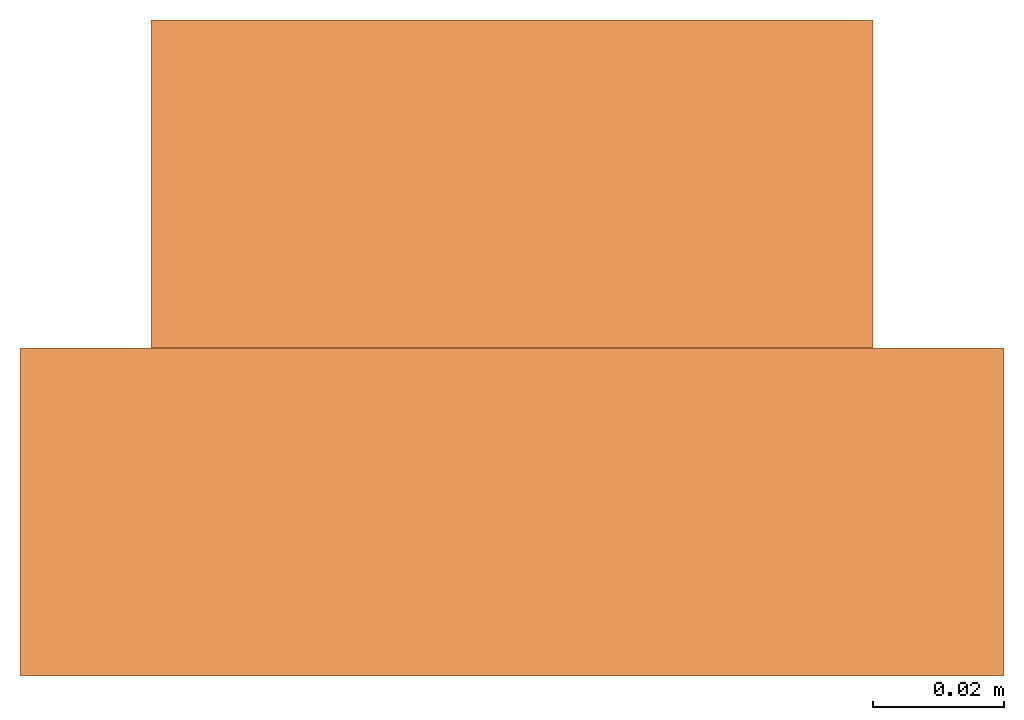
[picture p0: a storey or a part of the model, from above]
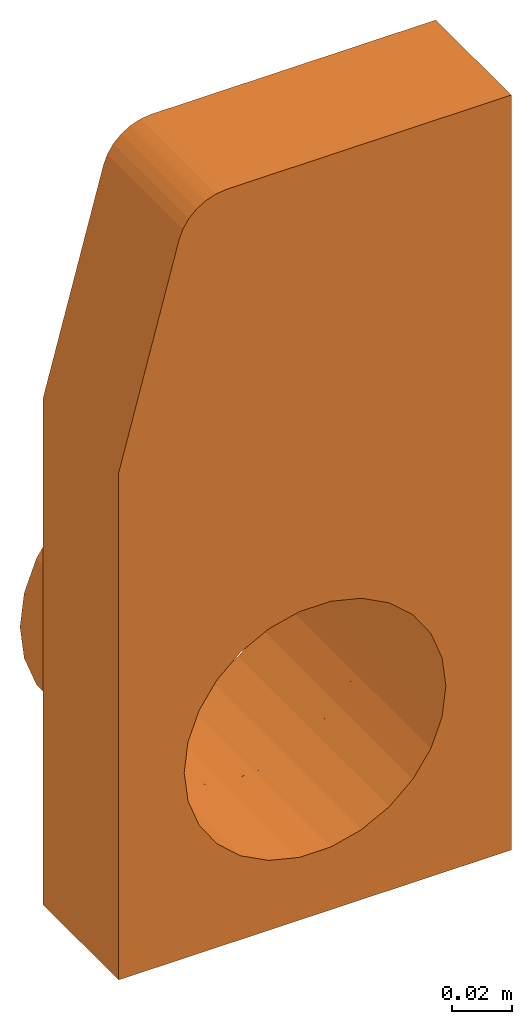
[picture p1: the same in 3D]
Properties of the parts of a building model (IFC2X3)

# File
Description: ViewDefinition [CoordinationView]
File name: 7963 - RH inlet or outlet end cap.ifc
Time: 2013-09-12T12:43:27
Written by: Autodesk Revit 2013
Made in: 20120221_2030(x64)

# IfcProject, Project Number
LongName: Project Name; Phase: Project Status

# IfcSite, Default
RefLatitude: 42, 21, 30, 344238; RefLongitude: -71, -3, -35, -194702; RefElevation: 0 mm

# IfcBuilding
Pset_BuildingCommon - NumberOfStoreys: 2
Other - Project Address: Enter address here; Project Number: Project Number; Client Name: Owner; Project Issue Date: Issue Date; Project Name: Project Name; Project Status: Project Status

# IfcBuildingStorey (2)
Constraints - Elevation Base: 0
Graphics - Line Pattern: Center; Color: 0; Symbol at End 2 Default: yes; Symbol at End 1 Default: no; Symbol: M_Level Head - Circle: M_Level Head - Circle; Line Weight: 1
Identity Data - Building Story: yes; Structural: no
Dimensions - Computation Height: 0 mm
Name | LongName = Name | Elevation (mm) = Constraints, Elevation (mm)
T.O. Fnd. Wall | T.O. Fnd. Wall | -300
Level 1 | Level 1 | 0

# IfcBuildingElementProxy: 7963 - RH inlet/outlet end cap, Civil-Drainage-Channel-ACO-KerbDrain-HB305 - PART 1:7963 - RH inlet/outlet end cap:7963 - RH inlet/outlet end cap:255899
In: T.O. Fnd. Wall
Material: ACO Polymer Concrete., Orange
Green Building Properties - Channel Recycled Material Content: N/A; Channel Recyclable: N/A; End Cap Recyclable: Fully recyclable; End Cap Recycled Material Content: 20% minimum; Access Cover/Frame Recyclable: N/A; Access Cover/Frame Recycled Material Content: N/A
Other - CreatedBy: www.aco.co.uk; Revision: 1
Dimensions - Void_Width: 150 mm; I/O Endcap Void depth: 230.003 mm; Staright Void Depth: -180 mm; Void_Length: 50 mm; Volume: 1908265 mm3
Constraints - Level: Level: Level 1; Moves With Nearby Elements: no
Phasing - Phase Created: Phase 1
Pset_BuildingElementProxyCommon - Reference: 7963 - RH inlet/outlet end cap
Materials and Finishes - Connection Pipe Material Colour: Brown; Access Cover/Frame Finish: N/A; End Cap Material: Vienite® Synthetic Resin Concrete; Connection Pipe Material: PVCu; Access Cover/Frame Material: N/A; Channel Material: N/A; End Cap Colour: Grey; Access Cover/Frame Colour: N/A; Channel Colour: N/A
Identity Data - Installation guidelines: http://www.aco.co.uk/download.php?id=120 http://www.aco.co.uk/download.php?id=120; Product Page URL: http://www.aco.co.uk/product_detail.php?id=3; Assembly Description: Rain Water Drainage; Assembly Code: D2040; Fax: +44 (0)1462 815895; Price: POA - contact ACO; Telephone: +44 (0)1462 816666; Maintenance guidelines: http://www.aco.co.uk/download.php?id=120; Cost: 0; Product Code: 7963; Address: ACO Business Park, Hitchin Road, Shefford, Bedfordshire, United Kingdom SG17 5TE; OmniClass Number: 23.70.50.24; Model Description: Combined kerb and drainage system; Type Comments: ACO KerbDrain HB305 half battered RH outlet end cap; Manufacturer: ACO Technologies plc - ACO Water Management Division; Product brochure: http://www.aco.co.uk/download.php?id=120; URL: www.aco.co.uk; Model: ACO KerbDrain HB305; E-mail Technical: technical@aco.co.uk; E-mail Sales: customersupport@aco.co.uk; OmniClass Title: Rainwater Removal
Construction - KDHB305 - RH drop kerb: no; KDHB305 - LH drop kerb: no; KDHB305 - Channel unit - 500mm: no; KDHB305 - Blind unit: no; KDHB305 - Flush RH dropkerb: no; KDHB305 - Closing end cap: no; KDHB305 - Flush LH dropkerb: no; KDHB305 - LH Inlet/Outlet end cap: no; KDHB305 - Access Unit: no; KDHB305 - Channel unit - 1000mm: no; KDHB305 - Centre stone: no; KDHB305 - Channel unit - 250mm: no; KDHB305 - Drainable centre stone: no; I/O Pipe: yes; KDHB305 - RH Inlet/outlet end cap: yes; KDHB305 - Perforated centre stone: no
General - SerialNumber: 0.000000; TagNumber: 0.000000
Data - Invert Depth: N/A; Product Standard: N/A; Load Class: N/A; Installation - Concrete Grade: N/A; ACO Hydraulic Design Software: N/A; Concrete Surround Volume - Load Class A 15 - D 400 - Concrete Pavement: N/A; Connection Pipe O.D: Ø110mm; Hydraulic Performance: N/A; Concrete Surround Volume - Load Class A 15 - D 400 - Grass or Asphalt Pavement: N/A; Product Weight: 3.9 Kg; Drainage Slot Width: N/A; Channel C.S.A: N/A; Drainage Slot Intake area: N/A; Product Dimensions: 50mm x 150mm x 305mm (LxWxH)

# IfcOpeningElement: Recess
In: Level 1
Structural - Enable Analytical Model: no; Structural: no
Dimensions - Thickness: 400 mm; Perimeter: 29157.2 mm; Volume: 21204611067 mm3; Area: 53016081 mm2
Constraints - Room Bounding: yes; Related to Mass: no; Level: Level: Level 1; Height Offset From Level: 0 mm
Phasing - Phase Created: Phase 1
Construction - Function: 0; Default Thickness: 400 mm
Analytical Properties - Absorptance: 0.1; Roughness: 1
Graphics - Coarse Scale Fill Color: 0

# IfcSlab: Floor:Generic Floor - 400mm, Floor:Generic Floor - 400mm:184025
In: Level 1
PredefinedType: FLOOR; Material: Default Floor 400 mm
Structural - Enable Analytical Model: no; Structural: no
Dimensions - Thickness: 400 mm; Perimeter: 29157.2 mm; Volume: 21204611067 mm3; Area: 53016081 mm2
Constraints - Room Bounding: yes; Related to Mass: no; Level: Level: Level 1; Height Offset From Level: 0 mm
Phasing - Phase Created: Phase 1
Pset_SlabCommon - Reference: Generic Floor - 400mm; IsExternal: no; LoadBearing: yes
Construction - Function: 0; Default Thickness: 400 mm
Analytical Properties - Absorptance: 0.1; Roughness: 1
Graphics - Coarse Scale Fill Color: 0
